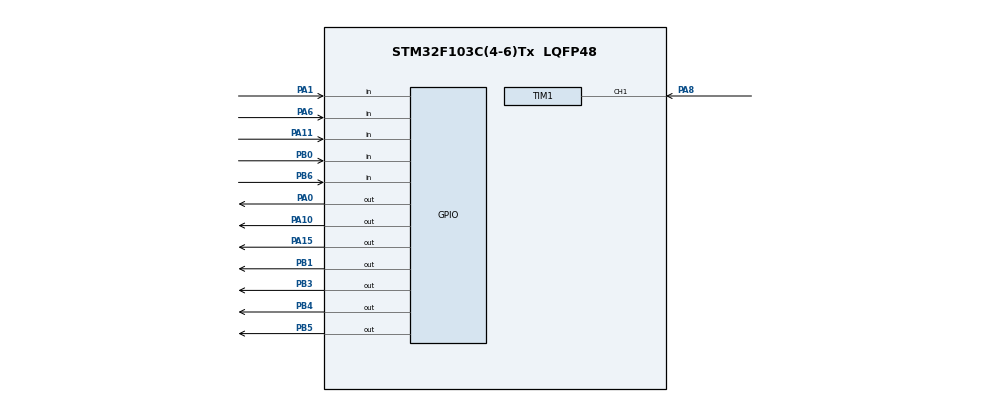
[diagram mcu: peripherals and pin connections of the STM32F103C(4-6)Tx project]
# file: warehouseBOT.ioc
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Mcu.Family=STM32F1
Mcu.Name=STM32F103C(4-6)Tx
Mcu.Package=LQFP48
NVIC.PriorityGroup=NVIC_PRIORITYGROUP_4
NVIC.TIM1_CC_IRQn=true\:0\:0\:false\:false\:true\:true\:true\:true
PA0-WKUP.Signal=GPIO_Output
PA1.Signal=GPIO_Input
PA10.Signal=GPIO_Output
PA11.Signal=GPIO_Input
PA13.Mode=Serial_Wire
PA13.Signal=SYS_JTMS-SWDIO
PA14.Mode=Serial_Wire
PA14.Signal=SYS_JTCK-SWCLK
PA15.Signal=GPIO_Output
PA6.Signal=GPIO_Input
PA8.Signal=S_TIM1_CH1
PB0.Signal=GPIO_Input
PB1.Signal=GPIO_Output
PB3.Signal=GPIO_Output
PB4.Signal=GPIO_Output
PB5.Signal=GPIO_Output
PB6.Signal=GPIO_Input
PC14-OSC32_IN.Mode=LSE-External-Oscillator
PC14-OSC32_IN.Signal=RCC_OSC32_IN
PC15-OSC32_OUT.Mode=LSE-External-Oscillator
PC15-OSC32_OUT.Signal=RCC_OSC32_OUT
PD0-OSC_IN.Mode=HSE-External-Oscillator
PD0-OSC_IN.Signal=RCC_OSC_IN
PD1-OSC_OUT.Mode=HSE-External-Oscillator
PD1-OSC_OUT.Signal=RCC_OSC_OUT
ProjectManager.HeapSize=0x200
ProjectManager.StackSize=0x400
ProjectManager.TargetToolchain=STM32CubeIDE
RCC.APB1Freq_Value=8000000
RCC.APB2Freq_Value=8000000
SH.S_TIM1_CH1.0=TIM1_CH1,Input_Capture1_from_TI1
TIM1.Channel-Input_Capture1_from_TI1=TIM_CHANNEL_1
board=custom

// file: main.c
/* USER CODE BEGIN Header */
/**
  ******************************************************************************
  * @file           : main.c
  * @brief          : Main program body
  ******************************************************************************
  * @attention
  *
  * Copyright (c) 2024 STMicroelectronics.
  * All rights reserved.
  *
  * This software is licensed under terms that can be found in the LICENSE file
  * in the root directory of this software component.
  * If no LICENSE file comes with this software, it is provided AS-IS.
  *
  ******************************************************************************
  */
/* USER CODE END Header */
#include "main.h"

TIM_HandleTypeDef htim1;

#define TRIG_PIN GPIO_PIN_5
#define TRIG_PORT GPIOB
#define ECHO_PIN GPIO_PIN_6
#define ECHO_PORT GPIOB

uint32_t Value1 = 0;
uint32_t Value2 = 0;

uint32_t pMillis;

uint32_t  Distance = 0;

void SystemClock_Config(void);
static void MX_GPIO_Init(void);
static void MX_TIM1_Init(void);

void Ultrasonic_Trigger(void);
//uint32_t Get_Ultrasonic_Distance(void);
void Robot_Stop(void);
void Robot_Move_Forward(void);
void Robot_Turn_Left(void);
void Robot_Turn_Right(void);

int main(void)
{

  /* MCU Configuration--------------------------------------------------------*/

  /* Reset of all peripherals, Initializes the Flash interface and the Systick. */
  HAL_Init();

  /* Configure the system clock */
  SystemClock_Config();

  /* Initialize all configured peripherals */
  MX_GPIO_Init();
  MX_TIM1_Init();
  /* USER CODE BEGIN 2 */
  HAL_TIM_Base_Start(&htim1);
  HAL_GPIO_WritePin(TRIG_PORT, TRIG_PIN, GPIO_PIN_RESET); // Ensure Trigger is LOW

  /* USER CODE END 2 */

  /* Infinite loop */
  /* USER CODE BEGIN WHILE */
  while (1) {
          // IR Sensor Logic
          int ir1 = HAL_GPIO_ReadPin(GPIOA, GPIO_PIN_6); // Left IR sensor
          int ir2 = HAL_GPIO_ReadPin(GPIOA, GPIO_PIN_1); // Right IR sensor

          HAL_GPIO_WritePin(TRIG_PORT, TRIG_PIN, GPIO_PIN_SET);  // Trigger HIGH
          __HAL_TIM_SET_COUNTER(&htim1, 0);
          while (__HAL_TIM_GET_COUNTER(&htim1) < 10); // Wait 10 us
          HAL_GPIO_WritePin(TRIG_PORT, TRIG_PIN, GPIO_PIN_RESET);  // Trigger LOW

          uint32_t pMillis = HAL_GetTick();
          while (!(HAL_GPIO_ReadPin(ECHO_PORT, ECHO_PIN)) && (pMillis + 10 > HAL_GetTick()));
          uint32_t Value1 = __HAL_TIM_GET_COUNTER(&htim1);

          pMillis = HAL_GetTick();
          while ((HAL_GPIO_ReadPin(ECHO_PORT, ECHO_PIN)) && (pMillis + 50 > HAL_GetTick()));
          uint32_t Value2 = __HAL_TIM_GET_COUNTER(&htim1);
          Distance = (Value2 - Value1) * 0.034 / 2; // Calculate distance in cm

          // Ultrasonic Distance
          //uint16_t Distance = Get_Ultrasonic_Distance();

          if (Distance <= 50) {
              // Obstacle detected: Stop and alert
              Robot_Stop();

        	  HAL_GPIO_WritePin(GPIOA, GPIO_PIN_15, GPIO_PIN_SET);  //7SEGMENT
        	  HAL_Delay(1000);
        	  HAL_GPIO_WritePin(GPIOB, GPIO_PIN_3, GPIO_PIN_SET);   //COUNT
        	  HAL_Delay(1000);
        	  HAL_GPIO_WritePin(GPIOB, GPIO_PIN_4, GPIO_PIN_SET);  //COUNT
        	  HAL_Delay(1000);
        	  HAL_GPIO_WritePin(GPIOA, GPIO_PIN_15, GPIO_PIN_RESET);  //7SEGMENT
        	  HAL_GPIO_WritePin(GPIOB, GPIO_PIN_3, GPIO_PIN_RESET);   //COUNT
        	  HAL_GPIO_WritePin(GPIOB, GPIO_PIN_4, GPIO_PIN_RESET);  //COUNT
          	  HAL_Delay(1000);
          	  HAL_GPIO_WritePin(GPIOA, GPIO_PIN_10, GPIO_PIN_SET); // Turn on buzzer

          } else {
              // Follow the Line
              HAL_GPIO_WritePin(GPIOA, GPIO_PIN_10, GPIO_PIN_RESET); // Ensure Buzzer OFF

              if (ir1 == 1 && ir2 == 1) {
                  Robot_Move_Forward(); // Both sensors detect black: Move forward
              } else if (ir1 == 1 && ir2 == 0) {
                  Robot_Turn_Right(); // Left sensor detects black: Turn right
              } else if (ir1 == 0 && ir2 == 1) {
                  Robot_Turn_Left(); // Right sensor detects black: Turn left
              } else {
                  Robot_Stop(); // Both sensors detect white: Stop
              }
          }

          // LDR Darkness Detection
          if (HAL_GPIO_ReadPin(GPIOB, GPIO_PIN_0) == 1) { // Assuming 0 indicates darkness
              HAL_GPIO_WritePin(GPIOA, GPIO_PIN_0, GPIO_PIN_SET); // LED ON
          } else {
              HAL_GPIO_WritePin(GPIOA, GPIO_PIN_0, GPIO_PIN_RESET); // LED OFF
          }

          // Gas Sensor Logic
          if (HAL_GPIO_ReadPin(GPIOA, GPIO_PIN_11) == 0) { // Flame or Gas detected
              HAL_GPIO_WritePin(GPIOA, GPIO_PIN_10, GPIO_PIN_SET); // Buzzer ON
              HAL_GPIO_WritePin(GPIOB, GPIO_PIN_1, GPIO_PIN_SET); // LED ON
              HAL_Delay(2000);
              HAL_GPIO_WritePin(GPIOA, GPIO_PIN_10, GPIO_PIN_RESET); // Buzzer OFF
              HAL_GPIO_WritePin(GPIOB, GPIO_PIN_1, GPIO_PIN_RESET); // LED OFF
          }

          HAL_Delay(10); // Stability Delay
      }
  }

  /* Ultrasonic Sensor Functions */
  void Ultrasonic_Trigger(void) {
      HAL_GPIO_WritePin(TRIG_PORT, TRIG_PIN, GPIO_PIN_SET); // Trigger HIGH
      __HAL_TIM_SET_COUNTER(&htim1, 0);
      while (__HAL_TIM_GET_COUNTER(&htim1) < 10); // 10us delay
      HAL_GPIO_WritePin(TRIG_PORT, TRIG_PIN, GPIO_PIN_RESET); // Trigger LOW
  }

  uint16_t Get_Ultrasonic_Distance(void) {
      Ultrasonic_Trigger();
      uint32_t timeout = HAL_GetTick();

      // Wait for ECHO to go HIGH
      while (!HAL_GPIO_ReadPin(ECHO_PORT, ECHO_PIN)) {
          if (HAL_GetTick() - timeout > 10) return 0xFFFF; // Timeout
      }
      Value1 = __HAL_TIM_GET_COUNTER(&htim1);

      // Wait for ECHO to go LOW
      timeout = HAL_GetTick();
      while (HAL_GPIO_ReadPin(ECHO_PORT, ECHO_PIN)) {
          if (HAL_GetTick() - timeout > 50) return 0xFFFF; // Timeout
      }
      Value2 = __HAL_TIM_GET_COUNTER(&htim1);

      return (Value2 - Value1) * 0.034 / 2; // Distance in cm
  }

  /* Robot Movement Functions */
  void Robot_Stop(void) {
      HAL_GPIO_WritePin(GPIOA, GPIO_PIN_4, GPIO_PIN_RESET);
      HAL_GPIO_WritePin(GPIOA, GPIO_PIN_5, GPIO_PIN_RESET);
      HAL_GPIO_WritePin(GPIOA, GPIO_PIN_2, GPIO_PIN_RESET);
      HAL_GPIO_WritePin(GPIOA, GPIO_PIN_3, GPIO_PIN_RESET);
  }

  void Robot_Move_Forward(void) {
      HAL_GPIO_WritePin(GPIOA, GPIO_PIN_4, GPIO_PIN_SET); // Left wheel forward
      HAL_GPIO_WritePin(GPIOA, GPIO_PIN_5, GPIO_PIN_SET); // Right wheel forward
      HAL_GPIO_WritePin(GPIOA, GPIO_PIN_2, GPIO_PIN_RESET); // Left wheel backward OFF
      HAL_GPIO_WritePin(GPIOA, GPIO_PIN_3, GPIO_PIN_RESET); // Right wheel backward OFF
  }

  void Robot_Turn_Left(void) {
      HAL_GPIO_WritePin(GPIOA, GPIO_PIN_4, GPIO_PIN_SET);
      HAL_GPIO_WritePin(GPIOA, GPIO_PIN_5, GPIO_PIN_RESET); // Right wheel forward
      HAL_GPIO_WritePin(GPIOA, GPIO_PIN_2, GPIO_PIN_RESET); // Left wheel backward
      HAL_GPIO_WritePin(GPIOA, GPIO_PIN_3, GPIO_PIN_RESET);
  }

  void Robot_Turn_Right(void) {
      HAL_GPIO_WritePin(GPIOA, GPIO_PIN_4, GPIO_PIN_RESET); // Left wheel forward
      HAL_GPIO_WritePin(GPIOA, GPIO_PIN_5, GPIO_PIN_SET);
      HAL_GPIO_WritePin(GPIOA, GPIO_PIN_2, GPIO_PIN_RESET);
      HAL_GPIO_WritePin(GPIOA, GPIO_PIN_3, GPIO_PIN_RESET); // Right wheel backward
  }  /* USER CODE END 3 */

void SystemClock_Config(void)
{
  RCC_OscInitTypeDef RCC_OscInitStruct = {0};
  RCC_ClkInitTypeDef RCC_ClkInitStruct = {0};

  /** Initializes the RCC Oscillators according to the specified parameters
  * in the RCC_OscInitTypeDef structure.
  */
  RCC_OscInitStruct.OscillatorType = RCC_OSCILLATORTYPE_HSI;
  RCC_OscInitStruct.HSIState = RCC_HSI_ON;
  RCC_OscInitStruct.HSICalibrationValue = RCC_HSICALIBRATION_DEFAULT;
  RCC_OscInitStruct.PLL.PLLState = RCC_PLL_NONE;
  if (HAL_RCC_OscConfig(&RCC_OscInitStruct) != HAL_OK)
  {
    Error_Handler();
  }

  /** Initializes the CPU, AHB and APB buses clocks
  */
  RCC_ClkInitStruct.ClockType = RCC_CLOCKTYPE_HCLK|RCC_CLOCKTYPE_SYSCLK
                              |RCC_CLOCKTYPE_PCLK1|RCC_CLOCKTYPE_PCLK2;
  RCC_ClkInitStruct.SYSCLKSource = RCC_SYSCLKSOURCE_HSI;
  RCC_ClkInitStruct.AHBCLKDivider = RCC_SYSCLK_DIV1;
  RCC_ClkInitStruct.APB1CLKDivider = RCC_HCLK_DIV1;
  RCC_ClkInitStruct.APB2CLKDivider = RCC_HCLK_DIV1;

  if (HAL_RCC_ClockConfig(&RCC_ClkInitStruct, FLASH_LATENCY_0) != HAL_OK)
  {
    Error_Handler();
  }
}

static void MX_TIM1_Init(void)
{

  TIM_ClockConfigTypeDef sClockSourceConfig = {0};
  TIM_MasterConfigTypeDef sMasterConfig = {0};
  TIM_IC_InitTypeDef sConfigIC = {0};

  htim1.Instance = TIM1;
  htim1.Init.Prescaler = 0;
  htim1.Init.CounterMode = TIM_COUNTERMODE_UP;
  htim1.Init.Period = 65535;
  htim1.Init.ClockDivision = TIM_CLOCKDIVISION_DIV1;
  htim1.Init.RepetitionCounter = 0;
  htim1.Init.AutoReloadPreload = TIM_AUTORELOAD_PRELOAD_DISABLE;
  if (HAL_TIM_Base_Init(&htim1) != HAL_OK)
  {
    Error_Handler();
  }
  sClockSourceConfig.ClockSource = TIM_CLOCKSOURCE_INTERNAL;
  if (HAL_TIM_ConfigClockSource(&htim1, &sClockSourceConfig) != HAL_OK)
  {
    Error_Handler();
  }
  if (HAL_TIM_IC_Init(&htim1) != HAL_OK)
  {
    Error_Handler();
  }
  sMasterConfig.MasterOutputTrigger = TIM_TRGO_RESET;
  sMasterConfig.MasterSlaveMode = TIM_MASTERSLAVEMODE_DISABLE;
  if (HAL_TIMEx_MasterConfigSynchronization(&htim1, &sMasterConfig) != HAL_OK)
  {
    Error_Handler();
  }
  sConfigIC.ICPolarity = TIM_INPUTCHANNELPOLARITY_RISING;
  sConfigIC.ICSelection = TIM_ICSELECTION_DIRECTTI;
  sConfigIC.ICPrescaler = TIM_ICPSC_DIV1;
  sConfigIC.ICFilter = 0;
  if (HAL_TIM_IC_ConfigChannel(&htim1, &sConfigIC, TIM_CHANNEL_1) != HAL_OK)
  {
    Error_Handler();
  }

}

static void MX_GPIO_Init(void)
{
  GPIO_InitTypeDef GPIO_InitStruct = {0};

  /* GPIO Ports Clock Enable */
  __HAL_RCC_GPIOC_CLK_ENABLE();
  __HAL_RCC_GPIOD_CLK_ENABLE();
  __HAL_RCC_GPIOA_CLK_ENABLE();
  __HAL_RCC_GPIOB_CLK_ENABLE();

  /*Configure GPIO pin Output Level */
  HAL_GPIO_WritePin(GPIOA, GPIO_PIN_0|GPIO_PIN_2|GPIO_PIN_3|GPIO_PIN_4
                          |GPIO_PIN_5|GPIO_PIN_10|GPIO_PIN_15, GPIO_PIN_RESET);

  /*Configure GPIO pin Output Level */
  HAL_GPIO_WritePin(GPIOB, GPIO_PIN_1|GPIO_PIN_3|GPIO_PIN_4|GPIO_PIN_5, GPIO_PIN_RESET);

  /*Configure GPIO pins : PA0 PA2 PA3 PA4
                           PA5 PA10 PA15 */
  GPIO_InitStruct.Pin = GPIO_PIN_0|GPIO_PIN_2|GPIO_PIN_3|GPIO_PIN_4
                          |GPIO_PIN_5|GPIO_PIN_10|GPIO_PIN_15;
  GPIO_InitStruct.Mode = GPIO_MODE_OUTPUT_PP;
  GPIO_InitStruct.Pull = GPIO_NOPULL;
  GPIO_InitStruct.Speed = GPIO_SPEED_FREQ_LOW;
  HAL_GPIO_Init(GPIOA, &GPIO_InitStruct);

  /*Configure GPIO pins : PA1 PA6 PA11 */
  GPIO_InitStruct.Pin = GPIO_PIN_1|GPIO_PIN_6|GPIO_PIN_11;
  GPIO_InitStruct.Mode = GPIO_MODE_INPUT;
  GPIO_InitStruct.Pull = GPIO_NOPULL;
  HAL_GPIO_Init(GPIOA, &GPIO_InitStruct);

  /*Configure GPIO pins : PB0 PB6 */
  GPIO_InitStruct.Pin = GPIO_PIN_0|GPIO_PIN_6;
  GPIO_InitStruct.Mode = GPIO_MODE_INPUT;
  GPIO_InitStruct.Pull = GPIO_NOPULL;
  HAL_GPIO_Init(GPIOB, &GPIO_InitStruct);

  /*Configure GPIO pins : PB1 PB3 PB4 PB5 */
  GPIO_InitStruct.Pin = GPIO_PIN_1|GPIO_PIN_3|GPIO_PIN_4|GPIO_PIN_5;
  GPIO_InitStruct.Mode = GPIO_MODE_OUTPUT_PP;
  GPIO_InitStruct.Pull = GPIO_NOPULL;
  GPIO_InitStruct.Speed = GPIO_SPEED_FREQ_LOW;
  HAL_GPIO_Init(GPIOB, &GPIO_InitStruct);

}

void Error_Handler(void)
{
  __disable_irq();
  while (1)
  {
  }
}
